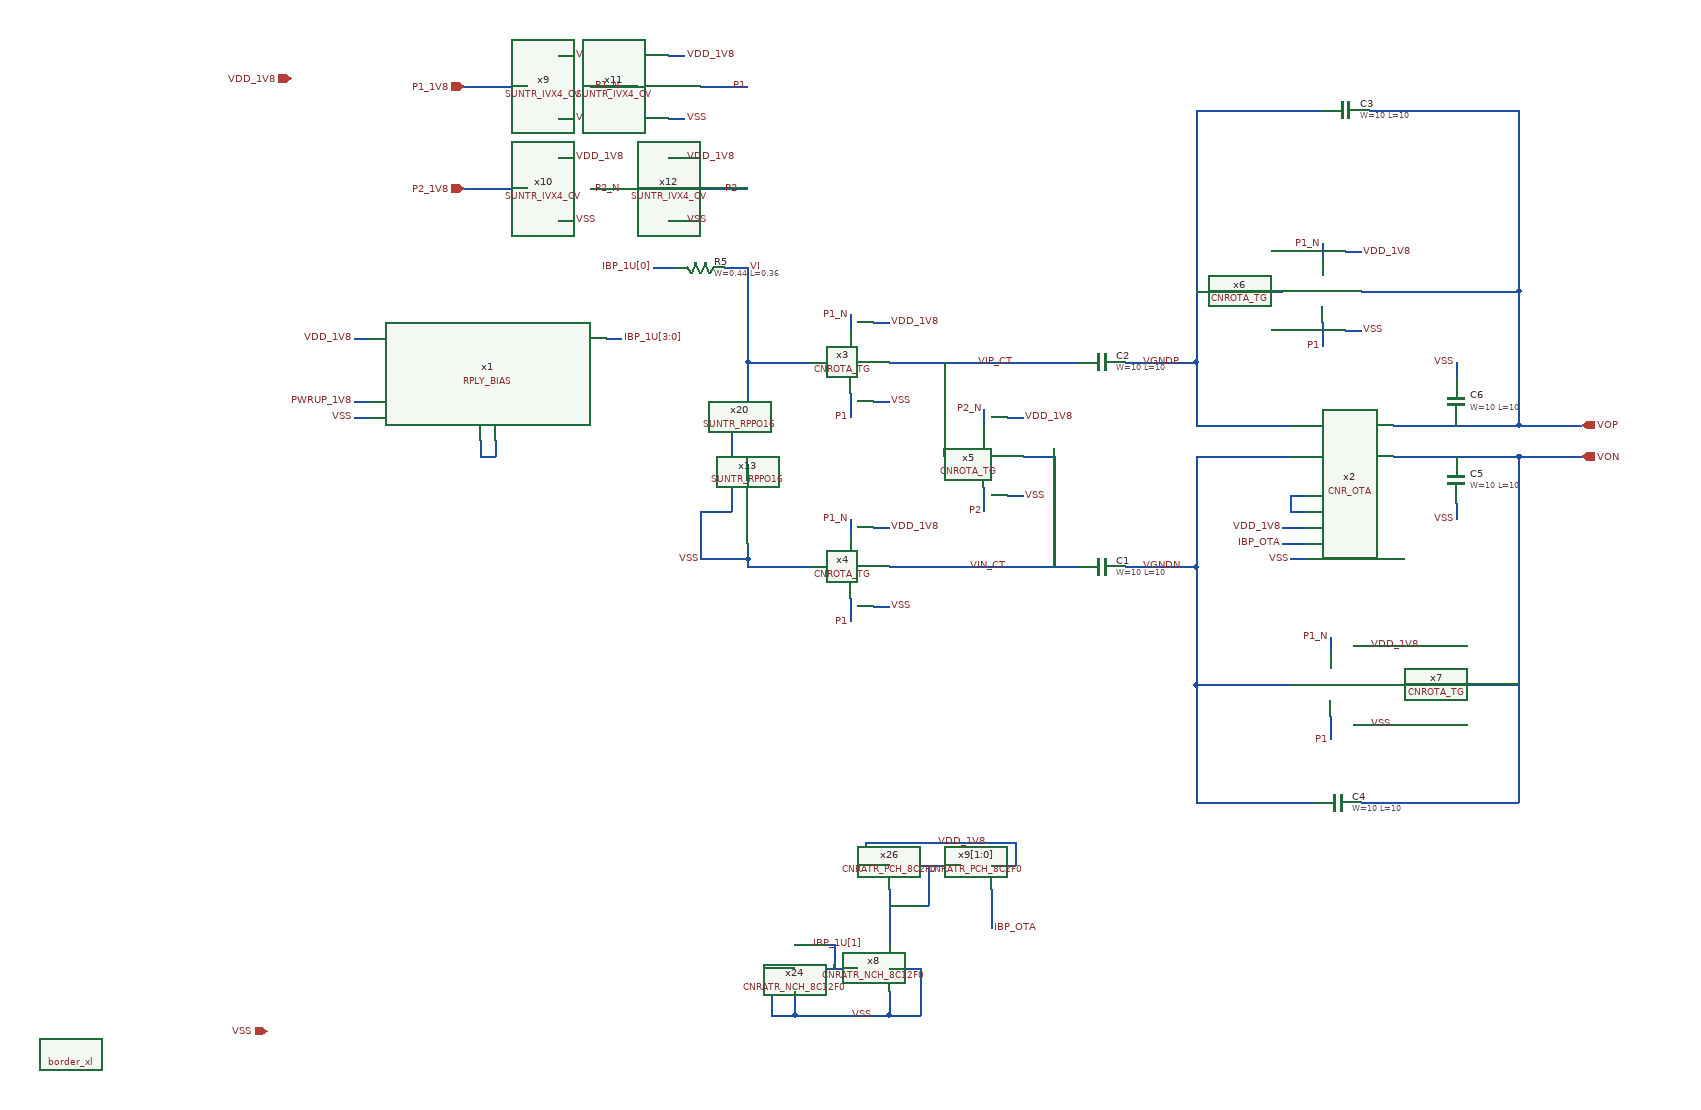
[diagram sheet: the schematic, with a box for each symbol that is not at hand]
v {xschem version=3.4.4 file_version=1.2
}
G {}
K {}
V {}
S {}
E {}
N 400 -770 400 -750 {
lab=#net1}
N 400 -750 420 -750 {
lab=#net1}
N 420 -770 420 -750 {
lab=#net1}
N 240 -800 260 -800 {
lab=VSS}
N 240 -820 260 -820 {
lab=PWRUP_1V8}
N 240 -900 260 -900 {
lab=VDD_1V8}
N 560 -900 580 -900 {
lab=IBP_1U[3:0]}
N 1430 -700 1450 -700 {
lab=#net2}
N 1430 -700 1430 -680 {
lab=#net2}
N 1430 -680 1450 -680 {
lab=#net2}
N 1430 -620 1450 -620 {
lab=VSS}
N 1420 -640 1450 -640 {
lab=IBP_OTA}
N 1420 -660 1450 -660 {
lab=VDD_1V8}
N 900 -920 920 -920 {
lab=VDD_1V8}
N 900 -820 920 -820 {
lab=VSS}
N 870 -830 870 -800 {
lab=P1}
N 870 -930 870 -910 {
lab=P1_N}
N 900 -660 920 -660 {
lab=VDD_1V8}
N 900 -560 920 -560 {
lab=VSS}
N 870 -570 870 -540 {
lab=P1}
N 870 -670 870 -650 {
lab=P1_N}
N 1070 -800 1090 -800 {
lab=VDD_1V8}
N 1070 -700 1090 -700 {
lab=VSS}
N 1040 -710 1040 -680 {
lab=P2}
N 1040 -810 1040 -790 {
lab=P2_N}
N 920 -870 1160 -870 {
lab=VIP_CT}
N 920 -610 1160 -610 {
lab=VIN_CT}
N 1500 -1010 1520 -1010 {
lab=VDD_1V8}
N 1500 -910 1520 -910 {
lab=VSS}
N 1470 -920 1470 -890 {
lab=P1}
N 1470 -1020 1470 -1000 {
lab=P1_N}
N 1510 -510 1530 -510 {
lab=VDD_1V8}
N 1510 -410 1530 -410 {
lab=VSS}
N 1480 -420 1480 -390 {
lab=P1}
N 1480 -520 1480 -500 {
lab=P1_N}
N 1310 -460 1430 -460 {
lab=VGNDN}
N 1310 -610 1310 -460 {
lab=VGNDN}
N 1220 -610 1310 -610 {
lab=VGNDN}
N 1310 -750 1430 -750 {
lab=VGNDN}
N 1310 -750 1310 -610 {
lab=VGNDN}
N 1310 -310 1460 -310 {
lab=VGNDN}
N 1310 -460 1310 -310 {
lab=VGNDN}
N 1520 -310 1720 -310 {
lab=VON}
N 1720 -750 1720 -310 {
lab=VON}
N 1560 -750 1720 -750 {
lab=VON}
N 1530 -460 1720 -460 {
lab=VON}
N 1310 -1190 1470 -1190 {
lab=VGNDP}
N 1310 -1190 1310 -870 {
lab=VGNDP}
N 1220 -870 1310 -870 {
lab=VGNDP}
N 1320 -960 1420 -960 {
lab=VGNDP}
N 1310 -790 1430 -790 {
lab=VGNDP}
N 1310 -870 1310 -790 {
lab=VGNDP}
N 1310 -960 1320 -960 {
lab=VGNDP}
N 1520 -960 1720 -960 {
lab=VOP}
N 1720 -960 1720 -790 {
lab=VOP}
N 1560 -790 1720 -790 {
lab=VOP}
N 1720 -1190 1720 -960 {
lab=VOP}
N 1530 -1190 1720 -1190 {
lab=VOP}
N 780 -870 820 -870 {
lab=VI}
N 780 -610 820 -610 {
lab=VSS}
N 1640 -870 1640 -850 {
lab=VSS}
N 1640 -690 1640 -670 {
lab=VSS}
N 920 -70 920 -40 {
lab=VSS}
N 800 -40 920 -40 {
lab=VSS}
N 800 -70 800 -40 {
lab=VSS}
N 770 -100 800 -100 {
lab=VSS}
N 770 -100 770 -40 {
lab=VSS}
N 770 -40 800 -40 {
lab=VSS}
N 920 -100 960 -100 {
lab=VSS}
N 960 -100 960 -40 {
lab=VSS}
N 920 -40 960 -40 {
lab=VSS}
N 840 -100 880 -100 {
lab=IBP_1U[1]}
N 800 -130 850 -130 {
lab=IBP_1U[1]}
N 850 -130 850 -100 {
lab=IBP_1U[1]}
N 920 -200 920 -130 {
lab=#net3}
N 890 -230 920 -230 {
lab=VDD_1V8}
N 890 -260 890 -230 {
lab=VDD_1V8}
N 890 -260 920 -260 {
lab=VDD_1V8}
N 920 -260 1050 -260 {
lab=VDD_1V8}
N 1050 -230 1080 -230 {
lab=VDD_1V8}
N 1080 -260 1080 -230 {
lab=VDD_1V8}
N 1050 -260 1080 -260 {
lab=VDD_1V8}
N 960 -230 1010 -230 {
lab=#net3}
N 960 -230 970 -230 {
lab=#net3}
N 970 -230 970 -180 {
lab=#net3}
N 920 -180 970 -180 {
lab=#net3}
N 1050 -200 1050 -150 {
lab=IBP_OTA}
N 680 -620 740 -620 {
lab=VSS}
N 680 -680 680 -620 {
lab=VSS}
N 1090 -750 1130 -750 {
lab=VIN_CT}
N 1130 -750 1130 -610 {
lab=VIN_CT}
N 990 -870 990 -750 {
lab=VIP_CT}
N 740 -870 780 -870 {
lab=VI}
N 740 -970 740 -870 {
lab=VI}
N 1720 -750 1800 -750 {
lab=VON}
N 1720 -790 1800 -790 {
lab=VOP}
N 380 -1090 460 -1090 {
lab=P2_1V8}
N 380 -1220 460 -1220 {
lab=P1_1V8}
N 500 -1260 520 -1260 {
lab=VDD_1V8}
N 500 -1180 520 -1180 {
lab=VSS}
N 500 -1050 520 -1050 {
lab=VSS}
N 500 -1130 520 -1130 {
lab=VDD_1V8}
N 640 -1260 660 -1260 {
lab=VDD_1V8}
N 640 -1180 660 -1180 {
lab=VSS}
N 540 -1220 600 -1220 {
lab=P1_N}
N 680 -1220 740 -1220 {
lab=P1}
N 640 -1130 660 -1130 {
lab=VDD_1V8}
N 640 -1050 660 -1050 {
lab=VSS}
N 680 -1090 740 -1090 {
lab=P2}
N 540 -1090 600 -1090 {
lab=P2_N}
N 740 -610 780 -610 {
lab=VSS}
N 740 -620 740 -610 {
lab=VSS}
N 740 -870 740 -820 {
lab=VI}
N 680 -680 720 -680 {
lab=VSS}
N 740 -740 740 -720 {
lab=#net4}
N 740 -640 740 -620 {
lab=VSS}
N 720 -780 720 -680 {
lab=VSS}
N 620 -990 650 -990 {
lab=IBP_1U[0]}
N 710 -990 740 -990 {
lab=VI}
N 740 -990 740 -970 {
lab=VI}
C {RPLY_BIAS_SKY130NM/RPLY_BIAS.sym} 410 -850 0 0 {name=x1}
C {devices/ipin.sym} 160 -1230 0 0 {name=p1 lab=VDD_1V8}
C {devices/ipin.sym} 130 -20 0 0 {name=p2 lab=VSS}
C {devices/lab_wire.sym} 240 -820 0 0 {name=p16 sig_type=std_logic lab=PWRUP_1V8}
C {devices/lab_wire.sym} 240 -800 0 0 {name=p3 sig_type=std_logic lab=VSS}
C {devices/lab_wire.sym} 240 -900 0 0 {name=p4 sig_type=std_logic lab=VDD_1V8}
C {devices/lab_wire.sym} 580 -900 0 1 {name=p5 sig_type=std_logic lab=IBP_1U[3:0]}
C {devices/lab_wire.sym} 680 -620 0 0 {name=p6 sig_type=std_logic lab=VSS}
C {CNR_OTA_SKY130NM/CNR_OTA.sym} 1560 -760 0 0 {name=x2}
C {devices/lab_wire.sym} 1430 -620 0 0 {name=p8 sig_type=std_logic lab=VSS}
C {devices/lab_wire.sym} 1420 -640 0 0 {name=p9 sig_type=std_logic lab=IBP_OTA}
C {devices/lab_wire.sym} 1420 -660 0 0 {name=p13 sig_type=std_logic lab=VDD_1V8}
C {sky130_fd_pr/cap_mim_m3_1.sym} 1190 -870 1 0 {name=C2 model=cap_mim_m3_1 W=10 L=10 MF=10 spiceprefix=X}
C {CNR_OTAEX_SKY130NM/CNROTA_TG.sym} 820 -870 0 0 {name=x3}
C {devices/lab_wire.sym} 920 -920 0 1 {name=p17 sig_type=std_logic lab=VDD_1V8}
C {devices/lab_wire.sym} 920 -820 0 1 {name=p18 sig_type=std_logic lab=VSS}
C {devices/lab_wire.sym} 870 -800 0 0 {name=p19 sig_type=std_logic lab=P1}
C {devices/lab_wire.sym} 870 -930 0 0 {name=p20 sig_type=std_logic lab=P1_N}
C {sky130_fd_pr/cap_mim_m3_1.sym} 1190 -610 1 0 {name=C1 model=cap_mim_m3_1 W=10 L=10 MF=10 spiceprefix=X}
C {CNR_OTAEX_SKY130NM/CNROTA_TG.sym} 820 -610 0 0 {name=x4}
C {devices/lab_wire.sym} 920 -660 0 1 {name=p21 sig_type=std_logic lab=VDD_1V8}
C {devices/lab_wire.sym} 920 -560 0 1 {name=p22 sig_type=std_logic lab=VSS}
C {devices/lab_wire.sym} 870 -540 0 0 {name=p23 sig_type=std_logic lab=P1}
C {devices/lab_wire.sym} 870 -670 0 0 {name=p24 sig_type=std_logic lab=P1_N}
C {CNR_OTAEX_SKY130NM/CNROTA_TG.sym} 990 -750 0 0 {name=x5}
C {devices/lab_wire.sym} 1090 -800 0 1 {name=p25 sig_type=std_logic lab=VDD_1V8}
C {devices/lab_wire.sym} 1090 -700 0 1 {name=p26 sig_type=std_logic lab=VSS}
C {devices/lab_wire.sym} 1040 -680 0 0 {name=p27 sig_type=std_logic lab=P2}
C {devices/lab_wire.sym} 1040 -810 0 0 {name=p28 sig_type=std_logic lab=P2_N}
C {sky130_fd_pr/cap_mim_m3_1.sym} 1500 -1190 1 0 {name=C3 model=cap_mim_m3_1 W=10 L=10 MF=2 spiceprefix=X}
C {CNR_OTAEX_SKY130NM/CNROTA_TG.sym} 1420 -960 0 0 {name=x6}
C {devices/lab_wire.sym} 1520 -1010 0 1 {name=p29 sig_type=std_logic lab=VDD_1V8}
C {devices/lab_wire.sym} 1520 -910 0 1 {name=p30 sig_type=std_logic lab=VSS}
C {devices/lab_wire.sym} 1470 -890 0 0 {name=p31 sig_type=std_logic lab=P1}
C {devices/lab_wire.sym} 1470 -1020 0 0 {name=p32 sig_type=std_logic lab=P1_N}
C {CNR_OTAEX_SKY130NM/CNROTA_TG.sym} 1430 -460 0 0 {name=x7}
C {devices/lab_wire.sym} 1530 -510 0 1 {name=p33 sig_type=std_logic lab=VDD_1V8}
C {devices/lab_wire.sym} 1530 -410 0 1 {name=p34 sig_type=std_logic lab=VSS}
C {devices/lab_wire.sym} 1480 -390 0 0 {name=p35 sig_type=std_logic lab=P1}
C {devices/lab_wire.sym} 1480 -520 0 0 {name=p36 sig_type=std_logic lab=P1_N}
C {sky130_fd_pr/cap_mim_m3_1.sym} 1490 -310 1 0 {name=C4 model=cap_mim_m3_1 W=10 L=10 MF=2 spiceprefix=X}
C {sky130_fd_pr/cap_mim_m3_1.sym} 1640 -720 0 0 {name=C5 model=cap_mim_m3_1 W=10 L=10 MF=20 spiceprefix=X}
C {sky130_fd_pr/cap_mim_m3_1.sym} 1640 -820 2 0 {name=C6 model=cap_mim_m3_1 W=10 L=10 MF=20 spiceprefix=X}
C {devices/lab_wire.sym} 1640 -870 1 0 {name=p39 sig_type=std_logic lab=VSS}
C {devices/lab_wire.sym} 1640 -670 3 0 {name=p40 sig_type=std_logic lab=VSS}
C {CNR_ATR_SKY130NM/CNRATR_NCH_8C12F0.sym} 840 -100 0 1 {name=x24 }
C {CNR_ATR_SKY130NM/CNRATR_NCH_8C12F0.sym} 880 -100 0 0 {name=x8 }
C {CNR_ATR_SKY130NM/CNRATR_PCH_8C2F0.sym} 960 -230 0 1 {name=x26 }
C {CNR_ATR_SKY130NM/CNRATR_PCH_8C2F0.sym} 1010 -230 0 0 {name=x9[1:0]}
C {devices/lab_wire.sym} 1050 -150 0 1 {name=p10 sig_type=std_logic lab=IBP_OTA}
C {devices/lab_wire.sym} 820 -130 0 1 {name=p11 sig_type=std_logic lab=IBP_1U[1]}
C {cborder/border_xl.sym} -120 10 0 0 {}
C {devices/opin.sym} 1800 -790 0 0 {name=p12 lab=VOP}
C {devices/opin.sym} 1800 -750 0 0 {name=p14 lab=VON}
C {devices/ipin.sym} 380 -1220 0 0 {name=p15 lab=P1_1V8}
C {devices/ipin.sym} 380 -1090 0 0 {name=p37 lab=P2_1V8}
C {SUN_TR_SKY130NM/SUNTR_IVX4_CV.sym} 460 -1220 0 0 {name=x9 }
C {SUN_TR_SKY130NM/SUNTR_IVX4_CV.sym} 460 -1090 0 0 {name=x10 }
C {devices/lab_wire.sym} 520 -1260 0 1 {name=p38 sig_type=std_logic lab=VDD_1V8}
C {devices/lab_wire.sym} 520 -1180 0 1 {name=p41 sig_type=std_logic lab=VSS}
C {devices/lab_wire.sym} 520 -1050 0 1 {name=p42 sig_type=std_logic lab=VSS}
C {devices/lab_wire.sym} 520 -1130 0 1 {name=p43 sig_type=std_logic lab=VDD_1V8}
C {SUN_TR_SKY130NM/SUNTR_IVX4_CV.sym} 600 -1220 0 0 {name=x11 }
C {devices/lab_wire.sym} 660 -1260 0 1 {name=p44 sig_type=std_logic lab=VDD_1V8}
C {devices/lab_wire.sym} 660 -1180 0 1 {name=p45 sig_type=std_logic lab=VSS}
C {SUN_TR_SKY130NM/SUNTR_IVX4_CV.sym} 600 -1090 0 0 {name=x12 }
C {devices/lab_wire.sym} 660 -1130 0 1 {name=p46 sig_type=std_logic lab=VDD_1V8}
C {devices/lab_wire.sym} 660 -1050 0 1 {name=p47 sig_type=std_logic lab=VSS}
C {devices/lab_wire.sym} 580 -1220 0 0 {name=p48 sig_type=std_logic lab=P1_N}
C {devices/lab_wire.sym} 740 -1220 0 0 {name=p49 sig_type=std_logic lab=P1}
C {devices/lab_wire.sym} 580 -1090 0 0 {name=p50 sig_type=std_logic lab=P2_N}
C {devices/lab_wire.sym} 730 -1090 0 0 {name=p51 sig_type=std_logic lab=P2}
C {devices/lab_wire.sym} 980 -260 0 1 {name=p52 sig_type=std_logic lab=VDD_1V8}
C {devices/lab_wire.sym} 870 -40 0 1 {name=p53 sig_type=std_logic lab=VSS}
C {devices/lab_wire.sym} 1030 -870 0 1 {name=p54 sig_type=std_logic lab=VIP_CT}
C {devices/lab_wire.sym} 1020 -610 0 1 {name=p55 sig_type=std_logic lab=VIN_CT}
C {devices/lab_wire.sym} 1240 -870 0 1 {name=p56 sig_type=std_logic lab=VGNDP}
C {devices/lab_wire.sym} 1240 -610 0 1 {name=p57 sig_type=std_logic lab=VGNDN}
C {SUN_TR_SKY130NM/SUNTR_RPPO16.sym} 740 -820 1 0 {name=x20 }
C {SUN_TR_SKY130NM/SUNTR_RPPO16.sym} 740 -720 1 0 {name=x13 }
C {sky130_fd_pr/res_generic_m3.sym} 680 -990 1 0 {name=R5
W=0.44
L=0.36
model=res_generic_m3
mult=1}
C {devices/lab_wire.sym} 620 -990 0 0 {name=p7 sig_type=std_logic lab=IBP_1U[0]}
C {devices/lab_wire.sym} 740 -990 0 1 {name=p58 sig_type=std_logic lab=VI}
